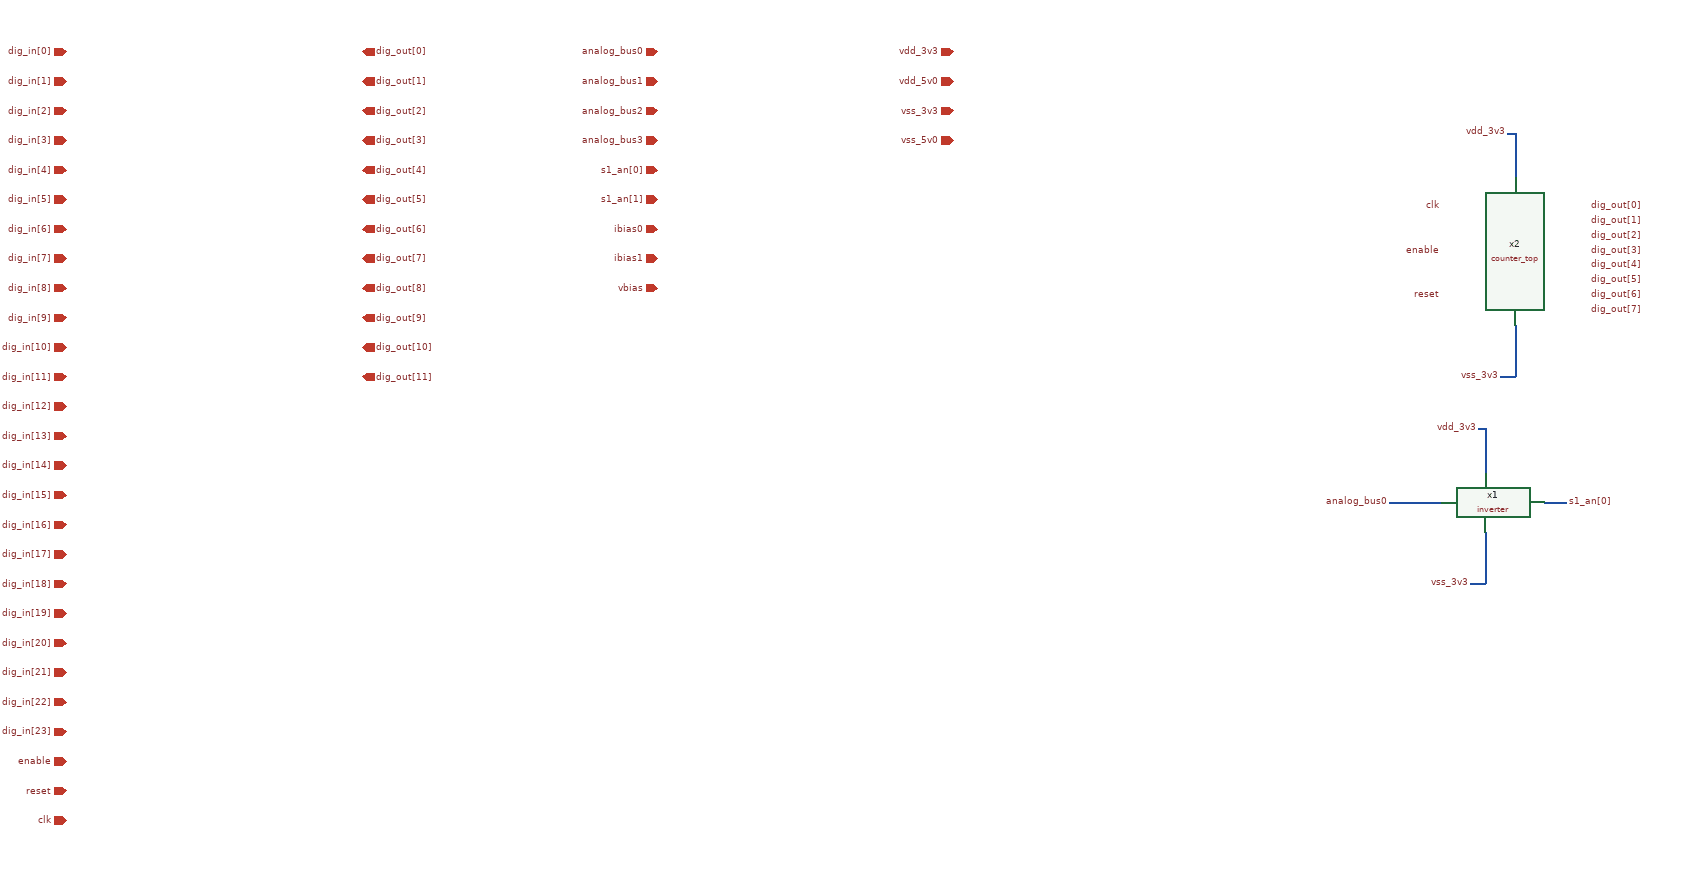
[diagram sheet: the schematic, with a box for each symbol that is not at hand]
v {xschem version=3.4.8RC file_version=1.3}
G {}
K {}
V {}
S {}
F {}
E {}
N 1910 510 1920 510 {lab=vdd_3v3}
N 1920 510 1920 570 {lab=vdd_3v3}
N 1900 720 1920 720 {lab=vss_3v3}
N 1920 650 1920 720 {lab=vss_3v3}
N 1790 610 1850 610 {lab=analog_bus0}
N 1850 610 1860 610 {lab=analog_bus0}
N 2000 610 2030 610 {lab=s1_an[0]}
N 1950 110 1960 110 {lab=vdd_3v3}
N 1960 110 1960 170 {lab=vdd_3v3}
N 1940 440 1960 440 {lab=vss_3v3}
N 1960 370 1960 440 {lab=vss_3v3}
C {ipin.sym} 0 0 0 0 {name=p1 lab=dig_in[0]}
C {ipin.sym} 0 40 0 0 {name=p2 lab=dig_in[1]}
C {ipin.sym} 0 80 0 0 {name=p3 lab=dig_in[2]}
C {ipin.sym} 0 120 0 0 {name=p4 lab=dig_in[3]}
C {ipin.sym} 0 160 0 0 {name=p5 lab=dig_in[4]}
C {ipin.sym} 0 200 0 0 {name=p6 lab=dig_in[5]}
C {ipin.sym} 0 240 0 0 {name=p7 lab=dig_in[6]}
C {ipin.sym} 0 280 0 0 {name=p8 lab=dig_in[7]}
C {ipin.sym} 0 320 0 0 {name=p9 lab=dig_in[8]}
C {ipin.sym} 0 360 0 0 {name=p10 lab=dig_in[9]}
C {ipin.sym} 0 400 0 0 {name=p11 lab=dig_in[10]}
C {ipin.sym} 0 440 0 0 {name=p12 lab=dig_in[11]}
C {ipin.sym} 0 480 0 0 {name=p13 lab=dig_in[12]}
C {ipin.sym} 0 520 0 0 {name=p14 lab=dig_in[13]}
C {ipin.sym} 0 560 0 0 {name=p15 lab=dig_in[14]}
C {ipin.sym} 0 600 0 0 {name=p16 lab=dig_in[15]}
C {ipin.sym} 0 640 0 0 {name=p17 lab=dig_in[16]}
C {ipin.sym} 0 680 0 0 {name=p18 lab=dig_in[17]}
C {ipin.sym} 0 720 0 0 {name=p19 lab=dig_in[18]}
C {ipin.sym} 0 760 0 0 {name=p20 lab=dig_in[19]}
C {ipin.sym} 0 800 0 0 {name=p21 lab=dig_in[20]}
C {ipin.sym} 0 840 0 0 {name=p22 lab=dig_in[21]}
C {ipin.sym} 0 880 0 0 {name=p23 lab=dig_in[22]}
C {ipin.sym} 0 920 0 0 {name=p24 lab=dig_in[23]}
C {ipin.sym} 0 960 0 0 {name=p25 lab=enable}
C {ipin.sym} 0 1000 0 0 {name=p26 lab=reset}
C {opin.sym} 400 0 0 0 {name=p27 lab=dig_out[0]}
C {opin.sym} 400 40 0 0 {name=p28 lab=dig_out[1]}
C {opin.sym} 400 80 0 0 {name=p29 lab=dig_out[2]}
C {opin.sym} 400 120 0 0 {name=p30 lab=dig_out[3]}
C {opin.sym} 400 160 0 0 {name=p31 lab=dig_out[4]}
C {opin.sym} 400 200 0 0 {name=p32 lab=dig_out[5]}
C {opin.sym} 400 240 0 0 {name=p33 lab=dig_out[6]}
C {opin.sym} 400 280 0 0 {name=p34 lab=dig_out[7]}
C {opin.sym} 400 320 0 0 {name=p35 lab=dig_out[8]}
C {opin.sym} 400 360 0 0 {name=p36 lab=dig_out[9]}
C {opin.sym} 400 400 0 0 {name=p37 lab=dig_out[10]}
C {opin.sym} 400 440 0 0 {name=p38 lab=dig_out[11]}
C {iopin.sym} 800 0 0 0 {name=p39 lab=analog_bus0}
C {iopin.sym} 800 40 0 0 {name=p40 lab=analog_bus1}
C {iopin.sym} 800 80 0 0 {name=p41 lab=analog_bus2}
C {iopin.sym} 800 120 0 0 {name=p42 lab=analog_bus3}
C {iopin.sym} 800 160 0 0 {name=p43 lab=s1_an[0]}
C {iopin.sym} 800 200 0 0 {name=p44 lab=s1_an[1]}
C {iopin.sym} 800 240 0 0 {name=p45 lab=ibias0}
C {iopin.sym} 800 280 0 0 {name=p46 lab=ibias1}
C {iopin.sym} 800 320 0 0 {name=p47 lab=vbias}
C {iopin.sym} 1200 0 0 0 {name=p48 lab=vdd_3v3}
C {iopin.sym} 1200 40 0 0 {name=p49 lab=vdd_5v0}
C {iopin.sym} 1200 80 0 0 {name=p50 lab=vss_3v3}
C {iopin.sym} 1200 120 0 0 {name=p51 lab=vss_5v0}
C {ipin.sym} 0 1040 0 0 {name=p52 lab=clk}
C {inverter.sym} 1920 610 0 0 {name=x1}
C {counter_top.sym} 1960 270 0 0 {name=x2}
C {lab_pin.sym} 1910 510 0 0 {name=p54 sig_type=std_logic lab=vdd_3v3}
C {lab_pin.sym} 1900 720 0 0 {name=p53 sig_type=std_logic lab=vss_3v3}
C {lab_pin.sym} 1790 610 0 0 {name=p56 sig_type=std_logic lab=analog_bus0}
C {lab_pin.sym} 2030 610 2 0 {name=p57 sig_type=std_logic lab=s1_an[0]}
C {lab_pin.sym} 1950 110 0 0 {name=p55 sig_type=std_logic lab=vdd_3v3}
C {lab_pin.sym} 1940 440 0 0 {name=p58 sig_type=std_logic lab=vss_3v3}
C {lab_pin.sym} 1860 210 0 0 {name=p62 sig_type=std_logic lab=clk}
C {lab_pin.sym} 1860 330 0 0 {name=p63 sig_type=std_logic lab=reset}
C {lab_pin.sym} 1860 270 0 0 {name=p64 sig_type=std_logic lab=enable}
C {noconn.sym} 1200 40 0 0 {name=l1}
C {noconn.sym} 1200 120 0 0 {name=l2}
C {noconn.sym} 800 40 0 0 {name=l3}
C {noconn.sym} 800 80 0 0 {name=l4}
C {noconn.sym} 800 120 0 0 {name=l5}
C {noconn.sym} 800 200 0 0 {name=l6}
C {noconn.sym} 800 240 0 0 {name=l7}
C {noconn.sym} 800 280 0 0 {name=l8}
C {noconn.sym} 800 320 0 0 {name=l9}
C {noconn.sym} 400 320 0 0 {name=l10}
C {noconn.sym} 400 360 0 0 {name=l11}
C {noconn.sym} 400 400 0 0 {name=l12}
C {noconn.sym} 400 440 0 0 {name=l13}
C {noconn.sym} 0 0 0 1 {name=l14}
C {noconn.sym} 0 40 0 1 {name=l15}
C {noconn.sym} 0 80 0 1 {name=l16}
C {noconn.sym} 0 120 0 1 {name=l17}
C {noconn.sym} 0 160 0 1 {name=l18}
C {noconn.sym} 0 200 0 1 {name=l19}
C {noconn.sym} 0 240 0 1 {name=l20}
C {noconn.sym} 0 280 0 1 {name=l21}
C {noconn.sym} 0 320 0 1 {name=l22}
C {noconn.sym} 0 360 0 1 {name=l23}
C {noconn.sym} 0 400 0 1 {name=l24}
C {noconn.sym} 0 440 0 1 {name=l25}
C {noconn.sym} 0 480 0 1 {name=l26}
C {noconn.sym} 0 520 0 1 {name=l27}
C {noconn.sym} 0 560 0 1 {name=l28}
C {noconn.sym} 0 600 0 1 {name=l29}
C {noconn.sym} 0 640 0 1 {name=l30}
C {noconn.sym} 0 680 0 1 {name=l31}
C {noconn.sym} 0 720 0 1 {name=l32}
C {noconn.sym} 0 760 0 1 {name=l33}
C {noconn.sym} 0 800 0 1 {name=l34}
C {noconn.sym} 0 840 0 1 {name=l35}
C {noconn.sym} 0 880 0 1 {name=l36}
C {noconn.sym} 0 920 0 1 {name=l37}
C {lab_pin.sym} 2060 210 2 0 {name=p59 sig_type=std_logic lab=dig_out[0]}
C {lab_pin.sym} 2060 230 2 0 {name=p60 sig_type=std_logic lab=dig_out[1]}
C {lab_pin.sym} 2060 250 2 0 {name=p61 sig_type=std_logic lab=dig_out[2]}
C {lab_pin.sym} 2060 270 2 0 {name=p66 sig_type=std_logic lab=dig_out[3]}
C {lab_pin.sym} 2060 290 2 0 {name=p67 sig_type=std_logic lab=dig_out[4]}
C {lab_pin.sym} 2060 310 2 0 {name=p68 sig_type=std_logic lab=dig_out[5]}
C {lab_pin.sym} 2060 330 2 0 {name=p69 sig_type=std_logic lab=dig_out[6]}
C {lab_pin.sym} 2060 350 2 0 {name=p70 sig_type=std_logic lab=dig_out[7]}
